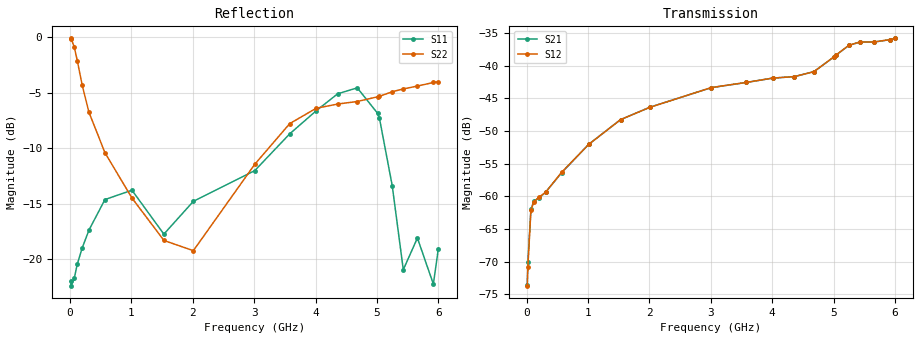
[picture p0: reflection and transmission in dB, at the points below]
!Agilent Technologies,N5230A,MY45001650,A.07.50.48
!Agilent N5230A: A.07.50.48
!Date: Saturday, July 08, 2017 15:52:30
!Correction: S11(Full 2 Port(1,2))
!S21(Full 2 Port(1,2))
!S12(Full 2 Port(1,2))
!S22(Full 2 Port(1,2))
!S2P File: Measurements: S11, S21, S12, S22:
# Hz S  dB  R 50
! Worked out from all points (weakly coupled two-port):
!   600 points, 10 MHz to 6 GHz, reference 50 ohm
!   highest |S21| = -35.81 dB at 6 GHz (marker M1); lowest = -73.6 dB at 10 MHz (marker M2)
!   lowest |S11| = -22.4 dB at 20 MHz (marker M3), VSWR 1.17, Z = 58.1 - j1.46 ohm
!   |S11| at or under -10 dB: start of sweep to 3.378 GHz; 5.162 GHz to end of sweep
!   |S22| runs from -19.7 to -0.1 dB; largest |S21 - S12| = 0.00027
!   S11 on the Smith chart (normalised r, x): 10 MHz: 1.17, -0.03; 1.53 GHz: 0.77, +0.05; 3.58 GHz: 0.76, +0.64; 4.36 GHz: 3.02, +1.15; 5.04 GHz: 1.36, -1.06; 6 GHz: 1.06, +0.22
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1e7  -21.97 -8.1  -73.61 14.8  -73.67 -65.4  -0.11 -5.5
2e7  -22.36 -9.4  -70.07 40.8  -70.83 25.7  -0.14 -10.5
7e7  -21.69 -27.3  -61.98 10.8  -62.06 7.7  -0.89 -34.7
1.2e8  -20.41 -42.7  -60.65 -20.1  -60.83 -20.5  -2.14 -53.9
2e8  -18.96 -65.5  -60.30 -54.1  -60.13 -53.2  -4.34 -77.2
3.1e8  -17.35 -92.6  -59.35 -82.5  -59.36 -82.6  -6.77 -98.9
5.7e8  -14.61 -135.7  -56.38 -124.7  -56.31 -124.8  -10.40 -129.7
1.01e9  -13.77 177.5  -52.04 -177.9  -52.05 -178.0  -14.47 -154.4
1.53e9  -17.72 166.3  -48.25 123.0  -48.25 123.0  -18.29 -170.0
2.01e9  -14.77 168.0  -46.34 70.1  -46.36 70.0  -19.21 -171.1
3.01e9  -12.01 138.3  -43.35 -31.6  -43.34 -31.5  -11.44 168.7
3.58e9  -8.70 90.6  -42.56 -87.5  -42.55 -87.5  -7.78 153.8
4.01e9  -6.63 40.5  -41.89 -128.5  -41.89 -128.5  -6.40 140.7
4.36e9  -5.10 13.7  -41.67 -160.1  -41.67 -160.1  -6.02 129.8
4.68e9  -4.56 -13.0  -40.90 176.7  -40.91 176.6  -5.79 117.2
5.01e9  -6.84 -43.6  -38.63 149.4  -38.61 149.3  -5.37 103.3
5.04e9  -7.25 -47.0  -38.38 146.3  -38.36 146.3  -5.33 101.4
5.25e9  -13.37 -64.1  -36.88 120.2  -36.87 120.2  -4.91 91.8
5.43e9  -20.92 -27.9  -36.38 95.9  -36.36 95.8  -4.66 81.8
5.66e9  -18.07 5.9  -36.37 68.8  -36.37 68.8  -4.40 69.9
5.92e9  -22.22 50.7  -36.01 42.5  -35.99 42.4  -4.08 56.8
6e9  -19.07 68.5  -35.81 34.1  -35.83 34.1  -4.01 52.3
